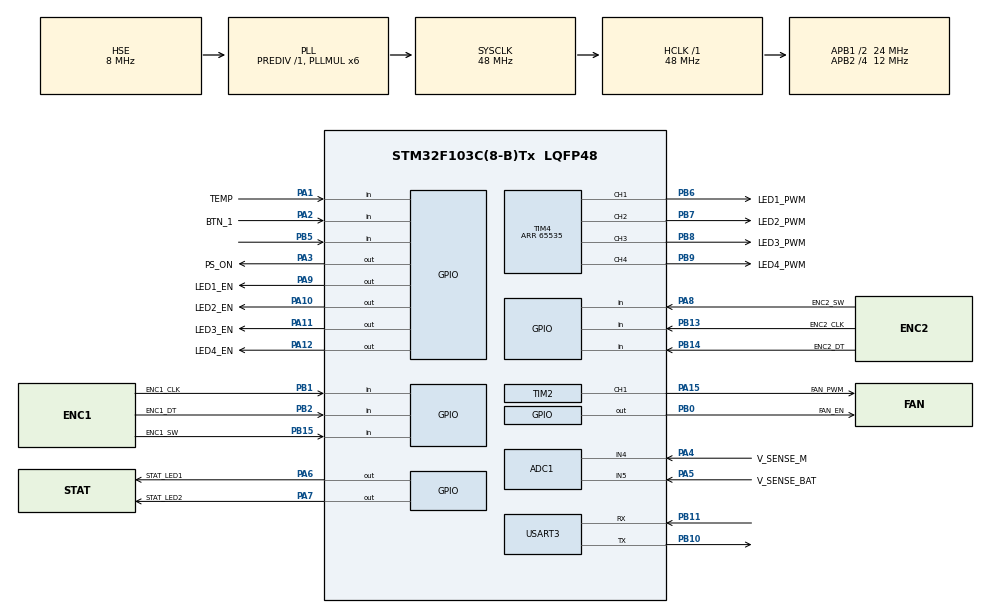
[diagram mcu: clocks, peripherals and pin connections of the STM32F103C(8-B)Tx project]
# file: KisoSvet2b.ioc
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ADC1.Channel-11\#ChannelInjectedConversion=ADC_CHANNEL_4
ADC1.Channel-12\#ChannelInjectedConversion=ADC_CHANNEL_5
ADC1.Channel-13\#ChannelRegularConversion=ADC_CHANNEL_4
ADC1.ContinuousConvMode=DISABLE
ADC1.DataAlign=ADC_DATAALIGN_RIGHT
ADC1.DiscontinuousConvMode=DISABLE
ADC1.EnableAnalogWatchDog=false
ADC1.EnableRegularConversion=ENABLE
ADC1.InjNumberOfConversion=2
ADC1.InjectedOffset-11\#ChannelInjectedConversion=0
ADC1.InjectedOffset-12\#ChannelInjectedConversion=0
ADC1.NbrOfConversionFlag=1
ADC1.Rank-11\#ChannelInjectedConversion=1
ADC1.Rank-12\#ChannelInjectedConversion=2
ADC1.Rank-13\#ChannelRegularConversion=1
ADC1.SamplingTime-11\#ChannelInjectedConversion=ADC_SAMPLETIME_1CYCLE_5
ADC1.SamplingTime-12\#ChannelInjectedConversion=ADC_SAMPLETIME_1CYCLE_5
ADC1.SamplingTime-13\#ChannelRegularConversion=ADC_SAMPLETIME_1CYCLE_5
ADC1.ScanConvMode=ADC_SCAN_ENABLE
ADC1.master=1
Mcu.Family=STM32F1
Mcu.Name=STM32F103C(8-B)Tx
Mcu.Package=LQFP48
NVIC.ADC1_2_IRQn=true\:0\:0\:false\:false\:true
NVIC.PriorityGroup=NVIC_PRIORITYGROUP_4
NVIC.USART3_IRQn=true\:0\:0\:false\:false\:true
PA1.GPIO_Label=TEMP
PA1.Signal=GPIO_Input
PA10.GPIO_Label=LED2_EN
PA10.GPIO_ModeDefaultOutputPP=GPIO_MODE_OUTPUT_PP
PA10.GPIO_Speed=GPIO_SPEED_FREQ_LOW
PA10.PinState=GPIO_PIN_SET
PA10.Signal=GPIO_Output
PA11.GPIO_Label=LED3_EN
PA11.GPIO_ModeDefaultOutputPP=GPIO_MODE_OUTPUT_PP
PA11.GPIO_Speed=GPIO_SPEED_FREQ_LOW
PA11.PinState=GPIO_PIN_SET
PA11.Signal=GPIO_Output
PA12.GPIO_Label=LED4_EN
PA12.GPIO_ModeDefaultOutputPP=GPIO_MODE_OUTPUT_PP
PA12.GPIO_Speed=GPIO_SPEED_FREQ_LOW
PA12.PinState=GPIO_PIN_SET
PA12.Signal=GPIO_Output
PA13.Mode=Serial_Wire
PA13.Signal=SYS_JTMS-SWDIO
PA14.Mode=Serial_Wire
PA14.Signal=SYS_JTCK-SWCLK
PA15.GPIO_Label=FAN_PWM
PA15.Signal=S_TIM2_CH1_ETR
PA2.GPIO_Label=BTN_1
PA2.Signal=GPIO_Input
PA3.GPIO_Label=PS_ON
PA3.GPIO_ModeDefaultOutputPP=GPIO_MODE_OUTPUT_PP
PA3.GPIO_Speed=GPIO_SPEED_FREQ_LOW
PA3.PinState=GPIO_PIN_SET
PA3.Signal=GPIO_Output
PA4.GPIO_Label=V_SENSE_M
PA4.Signal=ADCx_IN4
PA5.GPIO_Label=V_SENSE_BAT
PA5.Signal=ADCx_IN5
PA6.GPIO_Label=STAT_LED1
PA6.GPIO_ModeDefaultOutputPP=GPIO_MODE_OUTPUT_PP
PA6.GPIO_Speed=GPIO_SPEED_FREQ_LOW
PA6.PinState=GPIO_PIN_SET
PA6.Signal=GPIO_Output
PA7.GPIO_Label=STAT_LED2
PA7.GPIO_ModeDefaultOutputPP=GPIO_MODE_OUTPUT_PP
PA7.GPIO_Speed=GPIO_SPEED_FREQ_LOW
PA7.PinState=GPIO_PIN_SET
PA7.Signal=GPIO_Output
PA8.GPIO_Label=ENC2_SW
PA8.Signal=GPIO_Input
PA9.GPIO_Label=LED1_EN
PA9.GPIO_ModeDefaultOutputPP=GPIO_MODE_OUTPUT_PP
PA9.GPIO_Speed=GPIO_SPEED_FREQ_LOW
PA9.PinState=GPIO_PIN_SET
PA9.Signal=GPIO_Output
PB0.GPIO_Label=FAN_EN
PB0.GPIO_ModeDefaultOutputPP=GPIO_MODE_OUTPUT_PP
PB0.GPIO_Speed=GPIO_SPEED_FREQ_LOW
PB0.PinState=GPIO_PIN_SET
PB0.Signal=GPIO_Output
PB1.GPIO_Label=ENC1_CLK
PB1.Signal=GPIO_Input
PB10.Mode=Asynchronous
PB10.Signal=USART3_TX
PB11.Mode=Asynchronous
PB11.Signal=USART3_RX
PB13.GPIO_Label=ENC2_CLK
PB13.Signal=GPIO_Input
PB14.GPIO_Label=ENC2_DT
PB14.Signal=GPIO_Input
PB15.GPIO_Label=ENC1_SW
PB15.Signal=GPIO_Input
PB2.GPIO_Label=ENC1_DT
PB2.Signal=GPIO_Input
PB5.Signal=GPIO_Input
PB6.GPIO_Label=LED1_PWM
PB6.GPIO_Speed=GPIO_SPEED_FREQ_HIGH
PB6.Signal=S_TIM4_CH1
PB7.GPIO_Label=LED2_PWM
PB7.GPIO_Speed=GPIO_SPEED_FREQ_HIGH
PB7.Signal=S_TIM4_CH2
PB8.GPIO_Label=LED3_PWM
PB8.GPIO_Speed=GPIO_SPEED_FREQ_HIGH
PB8.Signal=S_TIM4_CH3
PB9.GPIO_Label=LED4_PWM
PB9.GPIO_Speed=GPIO_SPEED_FREQ_HIGH
PB9.Signal=S_TIM4_CH4
PC14-OSC32_IN.Mode=LSE-External-Oscillator
PC14-OSC32_IN.Signal=RCC_OSC32_IN
PC15-OSC32_OUT.Mode=LSE-External-Oscillator
PC15-OSC32_OUT.Signal=RCC_OSC32_OUT
PD0-OSC_IN.Mode=HSE-External-Oscillator
PD0-OSC_IN.Signal=RCC_OSC_IN
PD1-OSC_OUT.Mode=HSE-External-Oscillator
PD1-OSC_OUT.Signal=RCC_OSC_OUT
ProjectManager.HeapSize=0x200
ProjectManager.StackSize=0x400
ProjectManager.TargetToolchain=MDK-ARM V5
RCC.ADCPresc=RCC_ADCPCLK2_DIV6
RCC.AHBFreq_Value=48000000
RCC.APB1CLKDivider=RCC_HCLK_DIV2
RCC.APB1Freq_Value=24000000
RCC.APB1TimFreq_Value=48000000
RCC.APB2CLKDivider=RCC_HCLK_DIV4
RCC.APB2Freq_Value=12000000
RCC.APB2TimCLKDivider=2
RCC.APB2TimFreq_Value=24000000
RCC.HCLKFreq_Value=48000000
RCC.HSIState=RCC_HSI_ON
RCC.PLLMUL=RCC_PLL_MUL6
RCC.PLLSourceVirtual=RCC_PLLSOURCE_HSE
RCC.SYSCLKFreq_VALUE=48000000
RCC.SYSCLKSource=RCC_SYSCLKSOURCE_PLLCLK
RCC.USBFreq_Value=48000000
SH.ADCx_IN4.0=ADC1_IN4,IN4
SH.ADCx_IN5.0=ADC1_IN5,IN5
SH.S_TIM2_CH1_ETR.0=TIM2_CH1,PWM Generation1 CH1
SH.S_TIM4_CH1.0=TIM4_CH1,PWM Generation1 CH1
SH.S_TIM4_CH2.0=TIM4_CH2,PWM Generation2 CH2
SH.S_TIM4_CH3.0=TIM4_CH3,PWM Generation3 CH3
SH.S_TIM4_CH4.0=TIM4_CH4,PWM Generation4 CH4
TIM3.Period=1000
TIM3.Prescaler=7
TIM3.TIM_MasterOutputTrigger=TIM_TRGO_UPDATE
TIM4.Channel-PWM\ Generation2\ CH2=TIM_CHANNEL_2
TIM4.Channel-PWM\ Generation3\ CH3=TIM_CHANNEL_3
TIM4.Channel-PWM\ Generation4\ CH4=TIM_CHANNEL_4
TIM4.Period=65535
VP_RTC_VS_RTC_Activate.Mode=RTC_Enabled
VP_TIM3_VS_ClockSourceINT.Mode=Internal
board=KisoSvet2b

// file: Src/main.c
/**
  ******************************************************************************
  * File Name          : main.c
  * Description        : Main program body
  ******************************************************************************
  *
  * COPYRIGHT(c) 2016 STMicroelectronics
  *
  * Redistribution and use in source and binary forms, with or without modification,
  * are permitted provided that the following conditions are met:
  *   1. Redistributions of source code must retain the above copyright notice,
  *      this list of conditions and the following disclaimer.
  *   2. Redistributions in binary form must reproduce the above copyright notice,
  *      this list of conditions and the following disclaimer in the documentation
  *      and/or other materials provided with the distribution.
  *   3. Neither the name of STMicroelectronics nor the names of its contributors
  *      may be used to endorse or promote products derived from this software
  *      without specific prior written permission.
  *
  * THIS SOFTWARE IS PROVIDED BY THE COPYRIGHT HOLDERS AND CONTRIBUTORS "AS IS"
  * AND ANY EXPRESS OR IMPLIED WARRANTIES, INCLUDING, BUT NOT LIMITED TO, THE
  * IMPLIED WARRANTIES OF MERCHANTABILITY AND FITNESS FOR A PARTICULAR PURPOSE ARE
  * DISCLAIMED. IN NO EVENT SHALL THE COPYRIGHT HOLDER OR CONTRIBUTORS BE LIABLE
  * FOR ANY DIRECT, INDIRECT, INCIDENTAL, SPECIAL, EXEMPLARY, OR CONSEQUENTIAL
  * DAMAGES (INCLUDING, BUT NOT LIMITED TO, PROCUREMENT OF SUBSTITUTE GOODS OR
  * SERVICES; LOSS OF USE, DATA, OR PROFITS; OR BUSINESS INTERRUPTION) HOWEVER
  * CAUSED AND ON ANY THEORY OF? LIABILITY, WHETHER IN CONTRACT, STRICT LIABILITY,
  * OR TORT (INCLUDING NEGLIGENCE OR OTHERWISE) ARISING IN ANY WAY OUT OF THE USE
  * OF THIS SOFTWARE, EVEN IF ADVISED OF THE POSSIBILITY OF SUCH DAMAGE.
  *
  ******************************************************************************
  */
#include "main.h"
#include "stm32f1xx_hal.h"
#include "CLI.h"
#include "stdio.h"
#include "stm32f1xx.h"

ADC_HandleTypeDef hadc1;

RTC_HandleTypeDef hrtc;

TIM_HandleTypeDef htim2;
TIM_HandleTypeDef htim3;
TIM_HandleTypeDef htim4;

UART_HandleTypeDef huart3;
//EXTI_InitTypeDef EXTI_InitStruct;

/* USER CODE BEGIN PV */
/* Private variables ---------------------------------------------------------*/

	//configuration
short L_ECHO = 0;  //Local echo(CLI), to see what you type 1 - ON, 0 - OFF
short CMD_ANSWER = 1; //Write reply on command or not, not yet implemented

/* USER CODE END PV */

void Auxiliary(void);
void SystemClock_Config(void);
void Error_Handler(void);
void EXTI_Configuration(void);
static void MX_GPIO_Init(void);
static void MX_TIM4_Init(void);
static void MX_ADC1_Init(void);
static void MX_RTC_Init(void);
static void MX_TIM2_Init(void);
static void MX_TIM3_Init(void);
static void MX_USART3_UART_Init(void);
//void EXTI_Init(EXTI_InitTypeDef* EXTI_InitStruct);
void HAL_TIM_MspPostInit(TIM_HandleTypeDef *htim);
void HAL_ADCEx_InjectedConvCpltCallback(ADC_HandleTypeDef* hadc);
int LED_CVAL(int, int);
void LED_SW(void);
void CReturnCmd(void);
void GetTemperature(void);
void FlashTest(void); //debug
void ButtonFunctions(short btn_num, short btn_state); //Buttons functionality

/* USER CODE BEGIN PFP */
/* Private function prototypes -----------------------------------------------*/

/* USER CODE END PFP */

int main(void)
{

  /* MCU Configuration----------------------------------------------------------*/

  /* Reset of all peripherals, Initializes the Flash interface and the Systick. */
  HAL_Init();

  //* Configure the system clock */
  SystemClock_Config();

  /* Initialize all configured peripherals */
  MX_GPIO_Init();
  MX_TIM4_Init();
  MX_ADC1_Init();
  MX_RTC_Init();
  MX_TIM2_Init();
	MX_TIM3_Init();

  MX_USART3_UART_Init();
	__HAL_UART_ENABLE_IT(&huart3, UART_IT_RXNE);

	//TIM4 start(LED's PWM)
HAL_TIM_PWM_Start(&htim4, TIM_CHANNEL_1);
HAL_TIM_PWM_Start(&htim4, TIM_CHANNEL_2);
HAL_TIM_PWM_Start(&htim4, TIM_CHANNEL_3);
HAL_TIM_PWM_Start(&htim4, TIM_CHANNEL_4);

	//TIM2 start (FAN PWM)
HAL_TIM_PWM_Start(&htim2, TIM_CHANNEL_1);
	//TIM3 start
HAL_TIM_Base_Start(&htim3);

//GPIOExtiConfig(2, ButtonFunctions, (void*)1, BTN_1_Pin);

HAL_ADCEx_InjectedStart_IT(&hadc1); //start ADC
void GPIO_EXTILineConfig(uint8_t GPIO_PortSourceB, uint8_t GPIO_PinSource15); //EXTI for ENC1_SW
void GPIO_EXTILineConfig(uint8_t GPIO_PortSourceA, uint8_t GPIO_PinSource8); //EXTI for ENC2_SW

	//Sending greeting in terminal once after reset
printf("Meow! Kisosvet V2 has started \n\r");

  /* Infinite loop */
  /* USER CODE BEGIN WHILE */
  while (1)
  {

LED_SW();	//call LED on\off function
CReturnCmd(); //CLI functions
Auxiliary(); //Periferials function

  }

}

/** System Clock Configuration
*/
void SystemClock_Config(void)
{

  RCC_OscInitTypeDef RCC_OscInitStruct;
  RCC_ClkInitTypeDef RCC_ClkInitStruct;
  RCC_PeriphCLKInitTypeDef PeriphClkInit;

    /**Initializes the CPU, AHB and APB busses clocks
    */
  RCC_OscInitStruct.OscillatorType = RCC_OSCILLATORTYPE_LSI|RCC_OSCILLATORTYPE_HSE;
  RCC_OscInitStruct.HSEState = RCC_HSE_ON;
  RCC_OscInitStruct.HSEPredivValue = RCC_HSE_PREDIV_DIV1;
  RCC_OscInitStruct.HSIState = RCC_HSI_ON;
  RCC_OscInitStruct.LSIState = RCC_LSI_ON;
  RCC_OscInitStruct.PLL.PLLState = RCC_PLL_ON;
  RCC_OscInitStruct.PLL.PLLSource = RCC_PLLSOURCE_HSE;
  RCC_OscInitStruct.PLL.PLLMUL = RCC_PLL_MUL6;
  if (HAL_RCC_OscConfig(&RCC_OscInitStruct) != HAL_OK)
  {
    Error_Handler();
  }

    /**Initializes the CPU, AHB and APB busses clocks
    */
  RCC_ClkInitStruct.ClockType = RCC_CLOCKTYPE_HCLK|RCC_CLOCKTYPE_SYSCLK
                              |RCC_CLOCKTYPE_PCLK1|RCC_CLOCKTYPE_PCLK2;
  RCC_ClkInitStruct.SYSCLKSource = RCC_SYSCLKSOURCE_PLLCLK;
  RCC_ClkInitStruct.AHBCLKDivider = RCC_SYSCLK_DIV1;
  RCC_ClkInitStruct.APB1CLKDivider = RCC_HCLK_DIV2;
  RCC_ClkInitStruct.APB2CLKDivider = RCC_HCLK_DIV4;

  if (HAL_RCC_ClockConfig(&RCC_ClkInitStruct, FLASH_LATENCY_1) != HAL_OK)
  {
    Error_Handler();
  }

  PeriphClkInit.PeriphClockSelection = RCC_PERIPHCLK_RTC|RCC_PERIPHCLK_ADC;
  PeriphClkInit.RTCClockSelection = RCC_RTCCLKSOURCE_LSI;
  PeriphClkInit.AdcClockSelection = RCC_ADCPCLK2_DIV6;
  if (HAL_RCCEx_PeriphCLKConfig(&PeriphClkInit) != HAL_OK)
  {
    Error_Handler();
  }

    /**Configure the Systick interrupt time
    */
  HAL_SYSTICK_Config(HAL_RCC_GetHCLKFreq()/1000);

    /**Configure the Systick
    */
  HAL_SYSTICK_CLKSourceConfig(SYSTICK_CLKSOURCE_HCLK);

  /* SysTick_IRQn interrupt configuration */
  HAL_NVIC_SetPriority(SysTick_IRQn, 0, 0);
}

/* ADC1 init function */
static void MX_ADC1_Init(void)
{

  //ADC_ChannelConfTypeDef sConfig;
  ADC_InjectionConfTypeDef sConfigInjected;

    /**Common config
    */
  hadc1.Instance = ADC1;
  hadc1.Init.ScanConvMode = ADC_SCAN_ENABLE;
  hadc1.Init.ContinuousConvMode = DISABLE;
  hadc1.Init.DiscontinuousConvMode = DISABLE;
  hadc1.Init.ExternalTrigConv = ADC_SOFTWARE_START;
  hadc1.Init.DataAlign = ADC_DATAALIGN_RIGHT;
  hadc1.Init.NbrOfConversion = 2;
  if (HAL_ADC_Init(&hadc1) != HAL_OK)
  {
    Error_Handler();
  }

    /**Configure Injected Channel
    */
  sConfigInjected.InjectedChannel = ADC_CHANNEL_4;
  sConfigInjected.InjectedRank = 1;
  sConfigInjected.InjectedNbrOfConversion = 2;
  sConfigInjected.InjectedSamplingTime = ADC_SAMPLETIME_1CYCLE_5;
  sConfigInjected.ExternalTrigInjecConv = ADC_INJECTED_SOFTWARE_START;
  sConfigInjected.AutoInjectedConv = DISABLE;
  sConfigInjected.InjectedDiscontinuousConvMode = DISABLE;
  sConfigInjected.InjectedOffset = 0;
  if (HAL_ADCEx_InjectedConfigChannel(&hadc1, &sConfigInjected) != HAL_OK)
  {
    Error_Handler();
  }

    /**Configure Injected Channel
    */
	sConfigInjected.InjectedChannel = ADC_CHANNEL_5;
  sConfigInjected.InjectedRank = 2;
  if (HAL_ADCEx_InjectedConfigChannel(&hadc1, &sConfigInjected) != HAL_OK)
  {
    Error_Handler();
  }

}

/* RTC init function */
static void MX_RTC_Init(void)
{

    /**Initialize RTC Only
    */
  hrtc.Instance = RTC;
  hrtc.Init.AsynchPrediv = RTC_AUTO_1_SECOND;
  hrtc.Init.OutPut = RTC_OUTPUTSOURCE_ALARM;
  if (HAL_RTC_Init(&hrtc) != HAL_OK)
  {
    Error_Handler();
  }

}

/* TIM2 init function */
static void MX_TIM2_Init(void)
{

  TIM_MasterConfigTypeDef sMasterConfig;
  TIM_OC_InitTypeDef sConfigOC;

  htim2.Instance = TIM2;
  htim2.Init.Prescaler = 400000;
  htim2.Init.CounterMode = TIM_COUNTERMODE_UP;
  htim2.Init.Period = 255;
  htim2.Init.ClockDivision = TIM_CLOCKDIVISION_DIV1;
  if (HAL_TIM_PWM_Init(&htim2) != HAL_OK)
  {
    Error_Handler();
  }

  sMasterConfig.MasterOutputTrigger = TIM_TRGO_RESET;
  sMasterConfig.MasterSlaveMode = TIM_MASTERSLAVEMODE_DISABLE;
  if (HAL_TIMEx_MasterConfigSynchronization(&htim2, &sMasterConfig) != HAL_OK)
  {
    Error_Handler();
  }

  sConfigOC.OCMode = TIM_OCMODE_PWM1;
  sConfigOC.Pulse = 0;
  sConfigOC.OCPolarity = TIM_OCPOLARITY_HIGH;
  sConfigOC.OCFastMode = TIM_OCFAST_DISABLE;
  if (HAL_TIM_PWM_ConfigChannel(&htim2, &sConfigOC, TIM_CHANNEL_1) != HAL_OK)
  {
    Error_Handler();
  }

  HAL_TIM_MspPostInit(&htim2);

}
/* TIM4 init function */
static void MX_TIM3_Init(void)
{

  TIM_ClockConfigTypeDef sClockSourceConfig;
  TIM_MasterConfigTypeDef sMasterConfig;

  htim3.Instance = TIM3;
  htim3.Init.Prescaler = 70;
  htim3.Init.CounterMode = TIM_COUNTERMODE_UP;
  htim3.Init.Period = 1000;
  htim3.Init.ClockDivision = TIM_CLOCKDIVISION_DIV1;
  if (HAL_TIM_Base_Init(&htim3) != HAL_OK)
  {
    Error_Handler();
  }

  sClockSourceConfig.ClockSource = TIM_CLOCKSOURCE_INTERNAL;
  if (HAL_TIM_ConfigClockSource(&htim3, &sClockSourceConfig) != HAL_OK)
  {
    Error_Handler();
  }

  sMasterConfig.MasterOutputTrigger = TIM_TRGO_UPDATE;
  sMasterConfig.MasterSlaveMode = TIM_MASTERSLAVEMODE_DISABLE;
  if (HAL_TIMEx_MasterConfigSynchronization(&htim3, &sMasterConfig) != HAL_OK)
  {
    Error_Handler();
  }

}

/* TIM4 init function */
static void MX_TIM4_Init(void)
{

  TIM_MasterConfigTypeDef sMasterConfig;
  TIM_OC_InitTypeDef sConfigOC;

  htim4.Instance = TIM4;
  htim4.Init.Prescaler = 0;
  htim4.Init.CounterMode = TIM_COUNTERMODE_UP;
  htim4.Init.Period = 65535;
  htim4.Init.ClockDivision = TIM_CLOCKDIVISION_DIV1;
  if (HAL_TIM_PWM_Init(&htim4) != HAL_OK)
  {
    Error_Handler();
  }

  sMasterConfig.MasterOutputTrigger = TIM_TRGO_RESET;
  sMasterConfig.MasterSlaveMode = TIM_MASTERSLAVEMODE_DISABLE;
  if (HAL_TIMEx_MasterConfigSynchronization(&htim4, &sMasterConfig) != HAL_OK)
  {
    Error_Handler();
  }

  sConfigOC.OCMode = TIM_OCMODE_PWM1;
  sConfigOC.Pulse = 0;
  sConfigOC.OCPolarity = TIM_OCPOLARITY_HIGH;
  sConfigOC.OCFastMode = TIM_OCFAST_DISABLE;
  if (HAL_TIM_PWM_ConfigChannel(&htim4, &sConfigOC, TIM_CHANNEL_1) != HAL_OK)
  {
    Error_Handler();
  }

  if (HAL_TIM_PWM_ConfigChannel(&htim4, &sConfigOC, TIM_CHANNEL_2) != HAL_OK)
  {
    Error_Handler();
  }

  if (HAL_TIM_PWM_ConfigChannel(&htim4, &sConfigOC, TIM_CHANNEL_3) != HAL_OK)
  {
    Error_Handler();
  }

  if (HAL_TIM_PWM_ConfigChannel(&htim4, &sConfigOC, TIM_CHANNEL_4) != HAL_OK)
  {
    Error_Handler();
  }

  HAL_TIM_MspPostInit(&htim4);

}

/* USART3 init function */
static void MX_USART3_UART_Init(void)
{

  huart3.Instance = USART3;
  huart3.Init.BaudRate = 115200;
  huart3.Init.WordLength = UART_WORDLENGTH_8B;
  huart3.Init.StopBits = UART_STOPBITS_1;
  huart3.Init.Parity = UART_PARITY_NONE;
  huart3.Init.Mode = UART_MODE_TX_RX;
  huart3.Init.HwFlowCtl = UART_HWCONTROL_NONE;
  huart3.Init.OverSampling = UART_OVERSAMPLING_16;
  if (HAL_UART_Init(&huart3) != HAL_OK)
  {
    Error_Handler();
  }

}

/** Configure pins as
        * Analog
        * Input
        * Output
        * EVENT_OUT
        * EXTI
*/
static void MX_GPIO_Init(void)
{

  GPIO_InitTypeDef GPIO_InitStruct;

  /* GPIO Ports Clock Enable */
  __HAL_RCC_GPIOC_CLK_ENABLE();
  __HAL_RCC_GPIOD_CLK_ENABLE();
  __HAL_RCC_GPIOA_CLK_ENABLE();
  __HAL_RCC_GPIOB_CLK_ENABLE();

    /*Configure GPIO pin : TEMP_Pin */
  //GPIO_InitStruct.Pin = TEMP_Pin;
  //GPIO_InitStruct.Mode = GPIO_MODE_INPUT;
  //GPIO_InitStruct.Pull = GPIO_PULLDOWN; //try different
  HAL_GPIO_Init(TEMP_GPIO_Port, &GPIO_InitStruct);
		RCC->APB2ENR |=  RCC_APB2ENR_IOPAEN;  //Разрешить тактирование порта                          /
	GPIOA->CRL   &= ~GPIO_CRL_MODE1;      //Очистить биты MODE
	GPIOA->CRL   &= ~GPIO_CRL_CNF1;       //Очистить биты CNF
	GPIOA->CRL   |=  GPIO_CRL_MODE1_1 ;   //Выход,частота 2MHz
	GPIOA->CRL   |=  GPIO_CRL_CNF1_0;     //Открытый сток общего назначения
	GPIOA->ODR   |=  1<<1 ;               //отпустить шину
//

	  /*Configure GPIO pins : ENC2_SW */
  GPIO_InitStruct.Pin = GPIO_PIN_8;
  GPIO_InitStruct.Mode = GPIO_MODE_IT_FALLING;
	GPIO_InitStruct.Pull = GPIO_PULLUP;
  HAL_GPIO_Init(GPIOA, &GPIO_InitStruct);

	  /*Configure GPIO pins : BTN_1_Pin */
  GPIO_InitStruct.Pin = BTN_1_Pin;
  GPIO_InitStruct.Mode = GPIO_MODE_INPUT;
  //GPIO_InitStruct.Pull = GPIO_NOPULL;
	GPIO_InitStruct.Pull = GPIO_PULLUP;
  HAL_GPIO_Init(GPIOA, &GPIO_InitStruct);

		  /*Configure GPIO pins : ENC1_SW */
  GPIO_InitStruct.Pin = GPIO_PIN_15;
 	GPIO_InitStruct.Mode = GPIO_MODE_IT_FALLING;
	GPIO_InitStruct.Pull = GPIO_PULLUP;
  HAL_GPIO_Init(GPIOB, &GPIO_InitStruct);

  /*Configure GPIO pins : EXT_L_1_Pin STAT_LED1_Pin STAT_LED2_Pin LED1_EN_Pin
                           LED2_EN_Pin LED3_EN_Pin LED4_EN_Pin */
  GPIO_InitStruct.Pin = EXT_L_1_Pin|STAT_LED1_Pin|STAT_LED2_Pin|LED1_EN_Pin
                          |LED2_EN_Pin|LED3_EN_Pin|LED4_EN_Pin;
  GPIO_InitStruct.Mode = GPIO_MODE_OUTPUT_PP;
  GPIO_InitStruct.Speed = GPIO_SPEED_FREQ_LOW;
  HAL_GPIO_Init(GPIOA, &GPIO_InitStruct);

  /*Configure GPIO pin : STAT_LED3_Pin */
  GPIO_InitStruct.Pin = STAT_LED3_Pin;
  GPIO_InitStruct.Mode = GPIO_MODE_OUTPUT_PP;
  GPIO_InitStruct.Speed = GPIO_SPEED_FREQ_LOW;
  HAL_GPIO_Init(STAT_LED3_GPIO_Port, &GPIO_InitStruct);

  /*Configure GPIO pins : PB1 PB2 PB13 PB14
                         _Pin PB5 */
  GPIO_InitStruct.Pin = GPIO_PIN_1|GPIO_PIN_2|GPIO_PIN_13|GPIO_PIN_14|GPIO_PIN_5;
  GPIO_InitStruct.Mode = GPIO_MODE_INPUT;
  GPIO_InitStruct.Pull = GPIO_NOPULL;
  HAL_GPIO_Init(GPIOB, &GPIO_InitStruct);

  /*Configure GPIO pin Output Level */
  HAL_GPIO_WritePin(GPIOA, EXT_L_1_Pin|STAT_LED1_Pin|STAT_LED2_Pin, GPIO_PIN_RESET);
	//For LED_EN1-4
	HAL_GPIO_WritePin(GPIOA, LED1_EN_Pin|LED2_EN_Pin|LED3_EN_Pin|LED4_EN_Pin, GPIO_PIN_RESET);

  /*Configure GPIO pin Output Level */
  HAL_GPIO_WritePin(STAT_LED3_GPIO_Port, STAT_LED3_Pin, GPIO_PIN_SET);

 /* EXTI interrupt init*/
  HAL_NVIC_SetPriority(EXTI15_10_IRQn, 0, 0);
  HAL_NVIC_EnableIRQ(EXTI15_10_IRQn);

	HAL_NVIC_SetPriority(EXTI9_5_IRQn, 0, 0);
  HAL_NVIC_EnableIRQ(EXTI9_5_IRQn);
}

/* USER CODE BEGIN 4 */
void HAL_ADCEx_InjectedConvCpltCallback(ADC_HandleTypeDef* hadc)
{
AdcCh1Value = HAL_ADCEx_InjectedGetValue(&hadc1, ADC_INJECTED_RANK_1);
AdcCh2Value = HAL_ADCEx_InjectedGetValue(&hadc1, ADC_INJECTED_RANK_2);
HAL_ADCEx_InjectedStart_IT(&hadc1);
}

/* USER CODE END 4 */

void Error_Handler(void)
{
  while(1)
  {
  }
}

/************************ (C) COPYRIGHT STMicroelectronics *****END OF FILE****/
